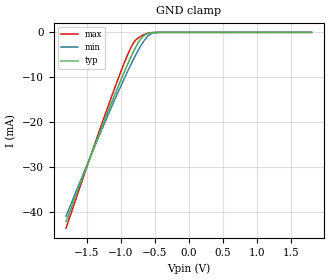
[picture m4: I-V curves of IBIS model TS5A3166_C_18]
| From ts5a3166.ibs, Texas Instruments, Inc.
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[Model]   TS5A3166_C_18
Model_type  Input
Vinl=0.6
Vinh=1.5
| variable   typ   min   max
C_comp   1.75pF   1.44pF   2.06pF
[Temperature Range]   40   100   -40
| Ambient temperature   25   85   -40
[Voltage range]   1.8   1.65   1.95
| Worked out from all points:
|   GND clamp passes 1 mA (typ) near -0.68 V on its own axis
[GND Clamp]
| TS5A3166_C_18
|   Voltage   I(typ)   I(min)   I(max)
-1.8V     -42.13mA   -40.92mA   -43.61mA
-1.35V    -24.03mA   -24.3mA    -23.6mA
-1.03V    -11.81mA   -13.07mA   -10.08mA
-930mV    -8.226mA   -9.739mA   -6.188mA
-855mV    -5.681mA   -7.34mA    -3.587mA
-800mV    -3.945mA   -5.659mA   -2.126mA
-750mV    -2.53mA    -4.214mA   -1.334mA
-680mV    -1.027mA   -2.396mA   -670.7uA
-610mV    -317.2uA   -994.2uA   -241.2uA
-555mV    -114.9uA   -348.2uA   -73.86uA
-485mV    -24.62uA   -60.82uA   -10.21uA
1.8V      29.06pA    89.02pA    18.04pA
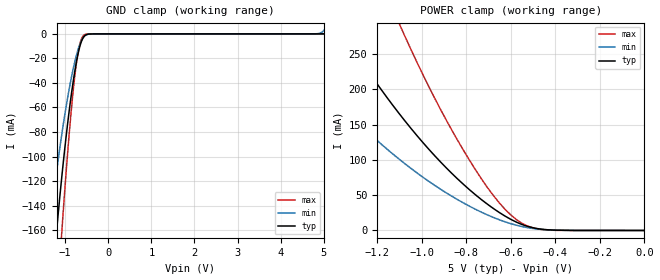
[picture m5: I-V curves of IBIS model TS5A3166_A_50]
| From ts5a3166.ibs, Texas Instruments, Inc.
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[Model]   TS5A3166_A_50
Model_type  Terminator
| variable   typ   min   max
C_comp   18.21pF   16.23pF   19.59pF
| C_tri-state   18.21pF   16.23pF   19.59pF
[Temperature Range]   40   100   -40
| Ambient temperature   25   85   -40
[Voltage range]   5   4.5   5.5
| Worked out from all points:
|   GND clamp passes 1 mA (typ) near -0.52 V on its own axis
|   POWER clamp passes 1 mA (typ) near -0.43 V on its own axis
[GND Clamp]
| TS5A3166_A_50
|   Voltage   I(typ)   I(min)   I(max)
-5V       -2.518A    -1.905A    -3.257A
-1.405V   -246.5mA   -171.6mA   -351.3mA
-1.36V    -226.8mA   -157.9mA   -323mA
-1.195V   -159.4mA   -111.2mA   -224.8mA
-1.075V   -115.6mA   -81.16mA   -160.2mA
-910mV    -63.85mA   -45.67mA   -83.26mA
-780mV    -31.36mA   -23.3mA    -35.55mA
-730mV    -21.32mA   -16.35mA   -21.93mA
-665mV    -10.99mA   -9.043mA   -9.186mA
-540mV    -1.374mA   -1.486mA   -515.1uA
4.78V     233.6pA    26.8uA     85.8pA
5V        1.594nA    2.789mA    92.39pA
[POWER Clamp]
| TS5A3166_A_50
|   Voltage   I(typ)   I(min)   I(max)
-5V       3.279A     2.411A     4.661A
-1.66V    447mA      282.6mA    762.6mA
-1.365V   285.6mA    177.2mA    498.6mA
-1.1V     165.2mA    100.8mA    292.5mA
-1.075V   155.2mA    94.49mA    274.9mA
-915mV    96.99mA    58.41mA    171.4mA
-780mV    56.3mA     33.5mA     96.83mA
-680mV    31.57mA    18.71mA    50.29mA
-575mV    11.89mA    7.485mA    15.55mA
-525mV    5.882mA    4.033mA    6.372mA
-460mV    1.744mA    1.414mA    1.305mA
-84.45fV  1.594nA    9.524nA    124pA
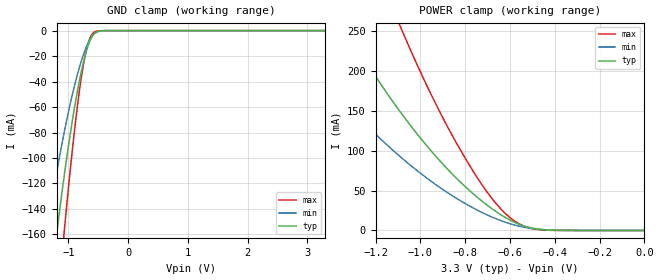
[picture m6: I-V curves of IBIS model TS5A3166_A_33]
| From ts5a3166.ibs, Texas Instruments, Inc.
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[Model]   TS5A3166_A_33
Model_type  Terminator
| variable   typ   min   max
C_comp   18.62pF   16.81pF   20.13pF
| C_tri-state   18.62pF   16.81pF   20.13pF
[Temperature Range]   40   100   -40
| Ambient temperature   25   85   -40
[Voltage range]   3.3   3   3.6
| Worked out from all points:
|   GND clamp passes 1 mA (typ) near -0.52 V on its own axis
|   POWER clamp passes 1 mA (typ) near -0.45 V on its own axis
[GND Clamp]
| TS5A3166_A_33
|   Voltage   I(typ)   I(min)   I(max)
-3.3V     -1.354A    -990.2mA   -1.817A
-1.375V   -232.7mA   -161.7mA   -331.9mA
-1.345V   -219.8mA   -152.7mA   -313.2mA
-1.195V   -158.9mA   -110.7mA   -224.4mA
-1.075V   -115.2mA   -80.7mA    -159.9mA
-905mV    -62.21mA   -44.41mA   -80.88mA
-780mV    -31.21mA   -23.12mA   -35.35mA
-730mV    -21.21mA   -16.21mA   -21.82mA
-670mV    -11.6mA    -9.439mA   -9.912mA
-620mV    -5.966mA   -5.263mA   -3.964mA
-555mV    -1.881mA   -1.936mA   -792.4uA
3.3V      962.6pA    34.74uA    60.66pA
[POWER Clamp]
| TS5A3166_A_33
|   Voltage   I(typ)   I(min)   I(max)
-3.3V     1.641A     1.142A     2.48A
-1.62V    401.2mA    256.3mA    675.9mA
-1.59V    384.5mA    245.2mA    649.1mA
-1.33V    251.2mA    158mA      430.4mA
-1.09V    148.6mA    92.46mA    255.8mA
-1.07V    141mA      87.68mA    242.7mA
-950mV    99mA       61.24mA    169.1mA
-815mV    58.91mA    36.23mA    97.8mA
-700mV    31.27mA    19.23mA    47.28mA
-600mV    13.07mA    8.468mA    16.08mA
-465mV    1.423mA    1.287mA    867.9uA
-48.03fV  962.6pA    7.174nA    77.06pA
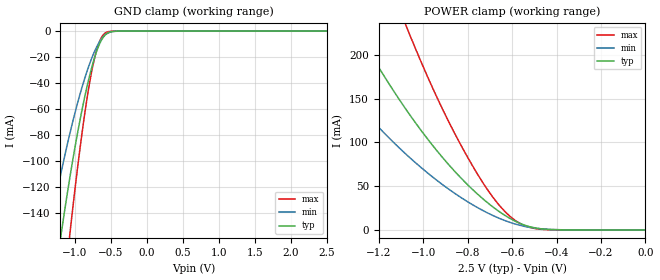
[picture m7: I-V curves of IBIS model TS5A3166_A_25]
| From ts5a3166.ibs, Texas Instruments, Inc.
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[Model]   TS5A3166_A_25
Model_type  Terminator
| variable   typ   min   max
C_comp   18.80pF   17.11pF   20.35pF
| C_tri-state   18.80pF   17.11pF   20.35pF
[Temperature Range]   40   100   -40
| Ambient temperature   25   85   -40
[Voltage range]   2.5   2.3   2.7
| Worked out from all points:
|   GND clamp passes 1 mA (typ) near -0.53 V on its own axis
|   POWER clamp passes 1 mA (typ) near -0.46 V on its own axis
[GND Clamp]
| TS5A3166_A_25
|   Voltage   I(typ)   I(min)   I(max)
-2.5V     -840.1mA   -600.1mA   -1.159A
-1.345V   -219.1mA   -152mA     -312.6mA
-1.195V   -158.4mA   -110.1mA   -223.9mA
-1.17V    -148.9mA   -103.6mA   -210mA
-1.065V   -111.4mA   -77.93mA   -154.4mA
-905mV    -61.94mA   -44.12mA   -80.48mA
-785mV    -32.13mA   -23.68mA   -36.63mA
-725mV    -20.19mA   -15.44mA   -20.52mA
-675mV    -12.22mA   -9.842mA   -10.66mA
-565mV    -2.292mA   -2.281mA   -1.043mA
-395mV    -34.14uA   -61.24uA   -3.165uA
2.5V      746.5pA    2.254uA    45.92pA
[POWER Clamp]
| TS5A3166_A_25
|   Voltage   I(typ)   I(min)   I(max)
-2.5V     969.5mA    652.7mA    1.529A
-1.565V   359.7mA    230.6mA    603.2mA
-1.3V     228.8mA    144.9mA    388.3mA
-1.075V   136.8mA    85.93mA    231.9mA
-1.055V   129.5mA    81.33mA    219.4mA
-905mV    80.35mA    50.25mA    133.8mA
-800mV    51.62mA    32.2mA     82.95mA
-690mV    27mA       16.94mA    38.61mA
-600mV    11.84mA    7.869mA    13.57mA
-540mV    5.17mA     3.876mA    4.537mA
-470mV    1.358mA    1.283mA    755uA
-31.15fV  746.5pA    6.247nA    56.76pA
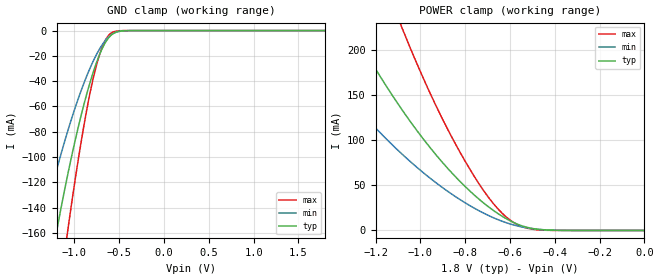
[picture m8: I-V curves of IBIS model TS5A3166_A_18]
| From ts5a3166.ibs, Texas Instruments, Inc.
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[Model]   TS5A3166_A_18
Model_type  Terminator
| variable   typ   min   max
C_comp   18.89pF   17.42pF   20.41pF
| C_tri-state   18.89pF   17.42pF   20.41pF
[Temperature Range]   40   100   -40
| Ambient temperature   25   85   -40
[Voltage range]   1.8   1.65   1.95
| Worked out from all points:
|   GND clamp passes 1 mA (typ) near -0.53 V on its own axis
|   POWER clamp passes 1 mA (typ) near -0.46 V on its own axis
[GND Clamp]
| TS5A3166_A_18
|   Voltage   I(typ)   I(min)   I(max)
-1.8V     -436.5mA   -304.8mA   -619.5mA
-1.37V    -228.7mA   -158.4mA   -326.9mA
-1.2V     -159.3mA   -110.5mA   -225.7mA
-1.08V    -115.7mA   -80.68mA   -161mA
-1.07V    -112.3mA   -78.35mA   -155.9mA
-915mV    -64.19mA   -45.51mA   -83.73mA
-795mV    -33.98mA   -24.85mA   -39.2mA
-740mV    -22.69mA   -17.1mA    -23.83mA
-685mV    -13.48mA   -10.68mA   -12.23mA
-580mV    -3.026mA   -2.865mA   -1.546mA
-400mV    -39.37uA   -69.03uA   -3.869uA
1.8V      589.7pA    482.3nA    32.73pA
[POWER Clamp]
| TS5A3166_A_18
|   Voltage   I(typ)   I(min)   I(max)
-1.8V     480.4mA    313.1mA    790.4mA
-1.555V   343.7mA    221.3mA    573.5mA
-1.3V     220.7mA    140.6mA    371.7mA
-1.18V    170.5mA    108.2mA    287.2mA
-1.075V   131mA      82.86mA    219.7mA
-950mV    89.56mA    56.52mA    148.2mA
-835mV    57.24mA    36.05mA    91.84mA
-720mV    30.84mA    19.47mA    44.88mA
-615mV    12.77mA    8.45mA     14.57mA
-555mV    5.859mA    4.312mA    5.134mA
-485mV    1.629mA    1.517mA    906.2uA
-16.28fV  589.7pA    5.47nA     40.44pA
